VERSION 5.7 ;
  NAMESCASESENSITIVE ON ;
  NOWIREEXTENSIONATPIN ON ;
  DIVIDERCHAR "/" ;
  BUSBITCHARS "[]" ;
UNITS
  DATABASE MICRONS 200 ;
END UNITS

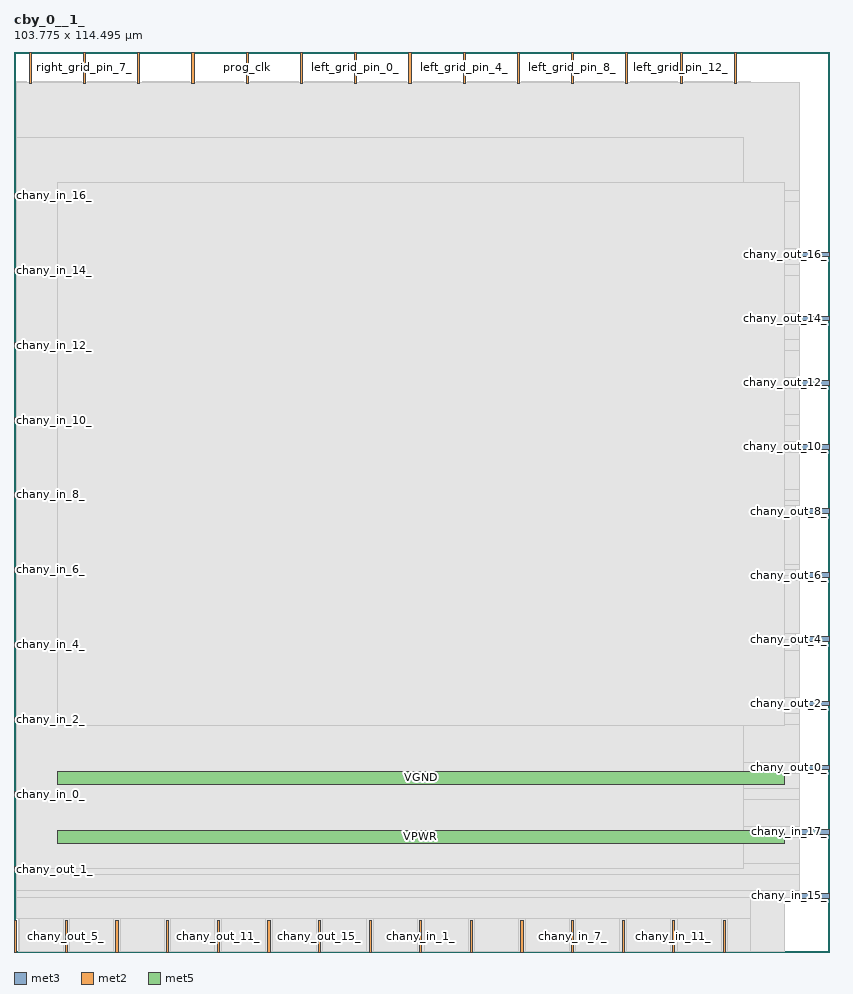
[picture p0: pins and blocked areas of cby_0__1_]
MACRO cby_0__1_
  CLASS BLOCK ;
  FOREIGN cby_0__1_ ;
  ORIGIN 0.000 0.000 ;
  SIZE 103.775 BY 114.495 ;
  PIN chany_out_1_
    DIRECTION OUTPUT TRISTATE ;
    PORT
      LAYER met3 ;
        RECT 0.000 10.240 4.000 10.840 ;
    END
  END chany_out_1_
  PIN chany_in_0_
    DIRECTION INPUT ;
    PORT
      LAYER met3 ;
        RECT 0.000 19.760 4.000 20.360 ;
    END
  END chany_in_0_
  PIN chany_in_2_
    DIRECTION INPUT ;
    PORT
      LAYER met3 ;
        RECT 0.000 29.280 4.000 29.880 ;
    END
  END chany_in_2_
  PIN chany_in_4_
    DIRECTION INPUT ;
    PORT
      LAYER met3 ;
        RECT 0.000 38.800 4.000 39.400 ;
    END
  END chany_in_4_
  PIN chany_in_6_
    DIRECTION INPUT ;
    PORT
      LAYER met3 ;
        RECT 0.000 48.320 4.000 48.920 ;
    END
  END chany_in_6_
  PIN chany_in_8_
    DIRECTION INPUT ;
    PORT
      LAYER met3 ;
        RECT 0.000 57.840 4.000 58.440 ;
    END
  END chany_in_8_
  PIN chany_in_10_
    DIRECTION INPUT ;
    PORT
      LAYER met3 ;
        RECT 0.000 67.360 4.000 67.960 ;
    END
  END chany_in_10_
  PIN chany_in_12_
    DIRECTION INPUT ;
    PORT
      LAYER met3 ;
        RECT 0.000 76.880 4.000 77.480 ;
    END
  END chany_in_12_
  PIN chany_in_14_
    DIRECTION INPUT ;
    PORT
      LAYER met3 ;
        RECT 0.000 86.400 4.000 87.000 ;
    END
  END chany_in_14_
  PIN chany_in_16_
    DIRECTION INPUT ;
    PORT
      LAYER met3 ;
        RECT 0.000 95.920 4.000 96.520 ;
    END
  END chany_in_16_
  PIN right_grid_pin_3_
    DIRECTION OUTPUT TRISTATE ;
    PORT
      LAYER met2 ;
        RECT 1.930 110.495 2.210 114.495 ;
    END
  END right_grid_pin_3_
  PIN right_grid_pin_7_
    DIRECTION OUTPUT TRISTATE ;
    PORT
      LAYER met2 ;
        RECT 8.830 110.495 9.110 114.495 ;
    END
  END right_grid_pin_7_
  PIN ccff_tail
    DIRECTION OUTPUT TRISTATE ;
    PORT
      LAYER met2 ;
        RECT 15.730 110.495 16.010 114.495 ;
    END
  END ccff_tail
  PIN ccff_head
    DIRECTION INPUT ;
    PORT
      LAYER met2 ;
        RECT 22.630 110.495 22.910 114.495 ;
    END
  END ccff_head
  PIN prog_clk
    DIRECTION INPUT ;
    PORT
      LAYER met2 ;
        RECT 29.530 110.495 29.810 114.495 ;
    END
  END prog_clk
  PIN pReset
    DIRECTION INPUT ;
    PORT
      LAYER met2 ;
        RECT 36.430 110.495 36.710 114.495 ;
    END
  END pReset
  PIN left_grid_pin_0_
    DIRECTION OUTPUT TRISTATE ;
    PORT
      LAYER met2 ;
        RECT 43.330 110.495 43.610 114.495 ;
    END
  END left_grid_pin_0_
  PIN left_grid_pin_2_
    DIRECTION OUTPUT TRISTATE ;
    PORT
      LAYER met2 ;
        RECT 50.230 110.495 50.510 114.495 ;
    END
  END left_grid_pin_2_
  PIN left_grid_pin_4_
    DIRECTION OUTPUT TRISTATE ;
    PORT
      LAYER met2 ;
        RECT 57.130 110.495 57.410 114.495 ;
    END
  END left_grid_pin_4_
  PIN left_grid_pin_6_
    DIRECTION OUTPUT TRISTATE ;
    PORT
      LAYER met2 ;
        RECT 64.030 110.495 64.310 114.495 ;
    END
  END left_grid_pin_6_
  PIN left_grid_pin_8_
    DIRECTION OUTPUT TRISTATE ;
    PORT
      LAYER met2 ;
        RECT 70.930 110.495 71.210 114.495 ;
    END
  END left_grid_pin_8_
  PIN left_grid_pin_10_
    DIRECTION OUTPUT TRISTATE ;
    PORT
      LAYER met2 ;
        RECT 77.830 110.495 78.110 114.495 ;
    END
  END left_grid_pin_10_
  PIN left_grid_pin_12_
    DIRECTION OUTPUT TRISTATE ;
    PORT
      LAYER met2 ;
        RECT 84.730 110.495 85.010 114.495 ;
    END
  END left_grid_pin_12_
  PIN left_grid_pin_14_
    DIRECTION OUTPUT TRISTATE ;
    PORT
      LAYER met2 ;
        RECT 91.630 110.495 91.910 114.495 ;
    END
  END left_grid_pin_14_
  PIN chany_in_15_
    DIRECTION INPUT ;
    PORT
      LAYER met3 ;
        RECT 99.775 6.840 103.775 7.440 ;
    END
  END chany_in_15_
  PIN chany_in_17_
    DIRECTION INPUT ;
    PORT
      LAYER met3 ;
        RECT 99.775 15.000 103.775 15.600 ;
    END
  END chany_in_17_
  PIN chany_out_0_
    DIRECTION OUTPUT TRISTATE ;
    PORT
      LAYER met3 ;
        RECT 99.775 23.160 103.775 23.760 ;
    END
  END chany_out_0_
  PIN chany_out_2_
    DIRECTION OUTPUT TRISTATE ;
    PORT
      LAYER met3 ;
        RECT 99.775 31.320 103.775 31.920 ;
    END
  END chany_out_2_
  PIN chany_out_4_
    DIRECTION OUTPUT TRISTATE ;
    PORT
      LAYER met3 ;
        RECT 99.775 39.480 103.775 40.080 ;
    END
  END chany_out_4_
  PIN chany_out_6_
    DIRECTION OUTPUT TRISTATE ;
    PORT
      LAYER met3 ;
        RECT 99.775 47.640 103.775 48.240 ;
    END
  END chany_out_6_
  PIN chany_out_8_
    DIRECTION OUTPUT TRISTATE ;
    PORT
      LAYER met3 ;
        RECT 99.775 55.800 103.775 56.400 ;
    END
  END chany_out_8_
  PIN chany_out_10_
    DIRECTION OUTPUT TRISTATE ;
    PORT
      LAYER met3 ;
        RECT 99.775 63.960 103.775 64.560 ;
    END
  END chany_out_10_
  PIN chany_out_12_
    DIRECTION OUTPUT TRISTATE ;
    PORT
      LAYER met3 ;
        RECT 99.775 72.120 103.775 72.720 ;
    END
  END chany_out_12_
  PIN chany_out_14_
    DIRECTION OUTPUT TRISTATE ;
    PORT
      LAYER met3 ;
        RECT 99.775 80.280 103.775 80.880 ;
    END
  END chany_out_14_
  PIN chany_out_16_
    DIRECTION OUTPUT TRISTATE ;
    PORT
      LAYER met3 ;
        RECT 99.775 88.440 103.775 89.040 ;
    END
  END chany_out_16_
  PIN chany_out_3_
    DIRECTION OUTPUT TRISTATE ;
    PORT
      LAYER met2 ;
        RECT 0.090 0.000 0.370 4.000 ;
    END
  END chany_out_3_
  PIN chany_out_5_
    DIRECTION OUTPUT TRISTATE ;
    PORT
      LAYER met2 ;
        RECT 6.530 0.000 6.810 4.000 ;
    END
  END chany_out_5_
  PIN chany_out_7_
    DIRECTION OUTPUT TRISTATE ;
    PORT
      LAYER met2 ;
        RECT 12.970 0.000 13.250 4.000 ;
    END
  END chany_out_7_
  PIN chany_out_9_
    DIRECTION OUTPUT TRISTATE ;
    PORT
      LAYER met2 ;
        RECT 19.410 0.000 19.690 4.000 ;
    END
  END chany_out_9_
  PIN chany_out_11_
    DIRECTION OUTPUT TRISTATE ;
    PORT
      LAYER met2 ;
        RECT 25.850 0.000 26.130 4.000 ;
    END
  END chany_out_11_
  PIN chany_out_13_
    DIRECTION OUTPUT TRISTATE ;
    PORT
      LAYER met2 ;
        RECT 32.290 0.000 32.570 4.000 ;
    END
  END chany_out_13_
  PIN chany_out_15_
    DIRECTION OUTPUT TRISTATE ;
    PORT
      LAYER met2 ;
        RECT 38.730 0.000 39.010 4.000 ;
    END
  END chany_out_15_
  PIN chany_out_17_
    DIRECTION OUTPUT TRISTATE ;
    PORT
      LAYER met2 ;
        RECT 45.170 0.000 45.450 4.000 ;
    END
  END chany_out_17_
  PIN chany_in_1_
    DIRECTION INPUT ;
    PORT
      LAYER met2 ;
        RECT 51.610 0.000 51.890 4.000 ;
    END
  END chany_in_1_
  PIN chany_in_3_
    DIRECTION INPUT ;
    PORT
      LAYER met2 ;
        RECT 58.050 0.000 58.330 4.000 ;
    END
  END chany_in_3_
  PIN chany_in_5_
    DIRECTION INPUT ;
    PORT
      LAYER met2 ;
        RECT 64.490 0.000 64.770 4.000 ;
    END
  END chany_in_5_
  PIN chany_in_7_
    DIRECTION INPUT ;
    PORT
      LAYER met2 ;
        RECT 70.930 0.000 71.210 4.000 ;
    END
  END chany_in_7_
  PIN chany_in_9_
    DIRECTION INPUT ;
    PORT
      LAYER met2 ;
        RECT 77.370 0.000 77.650 4.000 ;
    END
  END chany_in_9_
  PIN chany_in_11_
    DIRECTION INPUT ;
    PORT
      LAYER met2 ;
        RECT 83.810 0.000 84.090 4.000 ;
    END
  END chany_in_11_
  PIN chany_in_13_
    DIRECTION INPUT ;
    PORT
      LAYER met2 ;
        RECT 90.250 0.000 90.530 4.000 ;
    END
  END chany_in_13_
  PIN VPWR
    DIRECTION INPUT ;
    USE POWER ;
    PORT
      LAYER met5 ;
        RECT 5.520 13.840 97.980 15.440 ;
    END
  END VPWR
  PIN VGND
    DIRECTION INPUT ;
    USE GROUND ;
    PORT
      LAYER met5 ;
        RECT 5.520 21.340 97.980 22.940 ;
    END
  END VGND
  OBS
      LAYER li1 ;
        RECT 5.520 10.795 97.980 103.445 ;
      LAYER met1 ;
        RECT 0.530 0.040 97.980 103.600 ;
      LAYER met2 ;
        RECT 0.370 110.215 1.650 110.685 ;
        RECT 2.490 110.215 8.550 110.685 ;
        RECT 9.390 110.215 15.450 110.685 ;
        RECT 16.290 110.215 22.350 110.685 ;
        RECT 23.190 110.215 29.250 110.685 ;
        RECT 30.090 110.215 36.150 110.685 ;
        RECT 36.990 110.215 43.050 110.685 ;
        RECT 43.890 110.215 49.950 110.685 ;
        RECT 50.790 110.215 56.850 110.685 ;
        RECT 57.690 110.215 63.750 110.685 ;
        RECT 64.590 110.215 70.650 110.685 ;
        RECT 71.490 110.215 77.550 110.685 ;
        RECT 78.390 110.215 84.450 110.685 ;
        RECT 85.290 110.215 91.350 110.685 ;
        RECT 92.190 110.215 93.750 110.685 ;
        RECT 0.370 4.280 93.750 110.215 ;
        RECT 0.650 0.010 6.250 4.280 ;
        RECT 7.090 0.010 12.690 4.280 ;
        RECT 13.530 0.010 19.130 4.280 ;
        RECT 19.970 0.010 25.570 4.280 ;
        RECT 26.410 0.010 32.010 4.280 ;
        RECT 32.850 0.010 38.450 4.280 ;
        RECT 39.290 0.010 44.890 4.280 ;
        RECT 45.730 0.010 51.330 4.280 ;
        RECT 52.170 0.010 57.770 4.280 ;
        RECT 58.610 0.010 64.210 4.280 ;
        RECT 65.050 0.010 70.650 4.280 ;
        RECT 71.490 0.010 77.090 4.280 ;
        RECT 77.930 0.010 83.530 4.280 ;
        RECT 84.370 0.010 89.970 4.280 ;
        RECT 90.810 0.010 93.750 4.280 ;
      LAYER met3 ;
        RECT 0.270 96.920 99.970 110.665 ;
        RECT 4.400 95.520 99.970 96.920 ;
        RECT 0.270 89.440 99.970 95.520 ;
        RECT 0.270 88.040 99.375 89.440 ;
        RECT 0.270 87.400 99.970 88.040 ;
        RECT 4.400 86.000 99.970 87.400 ;
        RECT 0.270 81.280 99.970 86.000 ;
        RECT 0.270 79.880 99.375 81.280 ;
        RECT 0.270 77.880 99.970 79.880 ;
        RECT 4.400 76.480 99.970 77.880 ;
        RECT 0.270 73.120 99.970 76.480 ;
        RECT 0.270 71.720 99.375 73.120 ;
        RECT 0.270 68.360 99.970 71.720 ;
        RECT 4.400 66.960 99.970 68.360 ;
        RECT 0.270 64.960 99.970 66.960 ;
        RECT 0.270 63.560 99.375 64.960 ;
        RECT 0.270 58.840 99.970 63.560 ;
        RECT 4.400 57.440 99.970 58.840 ;
        RECT 0.270 56.800 99.970 57.440 ;
        RECT 0.270 55.400 99.375 56.800 ;
        RECT 0.270 49.320 99.970 55.400 ;
        RECT 4.400 48.640 99.970 49.320 ;
        RECT 4.400 47.920 99.375 48.640 ;
        RECT 0.270 47.240 99.375 47.920 ;
        RECT 0.270 40.480 99.970 47.240 ;
        RECT 0.270 39.800 99.375 40.480 ;
        RECT 4.400 39.080 99.375 39.800 ;
        RECT 4.400 38.400 99.970 39.080 ;
        RECT 0.270 32.320 99.970 38.400 ;
        RECT 0.270 30.920 99.375 32.320 ;
        RECT 0.270 30.280 99.970 30.920 ;
        RECT 4.400 28.880 99.970 30.280 ;
        RECT 0.270 24.160 99.970 28.880 ;
        RECT 0.270 22.760 99.375 24.160 ;
        RECT 0.270 20.760 99.970 22.760 ;
        RECT 4.400 19.360 99.970 20.760 ;
        RECT 0.270 16.000 99.970 19.360 ;
        RECT 0.270 14.600 99.375 16.000 ;
        RECT 0.270 11.240 99.970 14.600 ;
        RECT 4.400 9.840 99.970 11.240 ;
        RECT 0.270 7.840 99.970 9.840 ;
        RECT 0.270 6.975 99.375 7.840 ;
      LAYER met4 ;
        RECT 0.295 10.640 92.820 103.600 ;
      LAYER met5 ;
        RECT 5.520 28.840 97.980 97.940 ;
  END
END cby_0__1_
END LIBRARY

